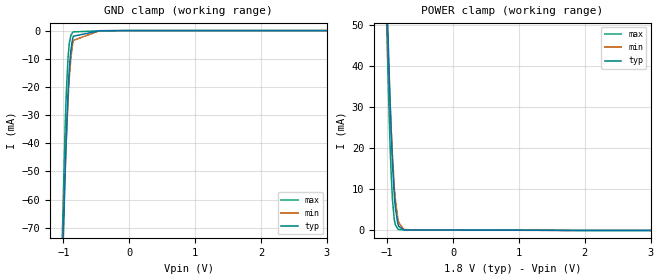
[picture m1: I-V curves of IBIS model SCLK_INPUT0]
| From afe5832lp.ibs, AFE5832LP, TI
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|   Model
[Model]   SCLK_INPUT0
Model_type   Input
Vinl = 0.45
Vinh = 1.35
|   typ   min   max
C_comp   1.431pF   1.417pF   1.444pF
[Voltage Range]   1.8   1.7   1.9
[Temperature Range]   25   85   -40
[Power Clamp Reference]   1.8   1.7   1.9
[GND Clamp Reference]   -0   -0   -0
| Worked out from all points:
|   POWER clamp passes 1 mA (typ) near -0.82 V on its own axis
[GND Clamp]
|   Voltage   I(typ)   I(min)   I(max)
-1.8V     -1.008A    -896.8mA   -1.105A
-1.017V   -87.02mA   -81.01mA   -72.85mA
-979.2mV  -54.6mA    -53.08mA   -38.24mA
-968.4mV  -46.35mA   -45.94mA   -30.03mA
-957.6mV  -38.67mA   -39.26mA   -22.79mA
-930.6mV  -22.47mA   -24.85mA   -9.685mA
-909mV    -13.08mA   -16mA      -4.192mA
-887.4mV  -6.947mA   -9.631mA   -1.721mA
-860.4mV  -2.882mA   -4.724mA   -628.3uA
-849.6mV  -2.005mA   -3.495mA   -455.1uA
-450mV    -65.8uA    -46.8uA    -96.36uA
3.595V    0A         0A         0A
[POWER Clamp]
|   Voltage   I(typ)   I(min)   I(max)
-1.8V     623.1mA    541mA      704mA
-1.006V   57.87mA    53.4mA     49.26mA
-1.001V   54.8mA     50.81mA    45.81mA
-968.4mV  37.48mA    36.16mA    26.85mA
-957.6mV  32.21mA    31.69mA    21.42mA
-941.4mV  24.92mA    25.43mA    14.38mA
-919.8mV  16.57mA    18.11mA    7.432mA
-892.8mV  8.753mA    10.84mA    2.687mA
-876.6mV  5.561mA    7.58mA     1.386mA
-838.8mV  1.662mA    2.886mA    353.2uA
-747mV    139.6uA    230.6uA    148.4uA
3.595V    0A         0A         0A
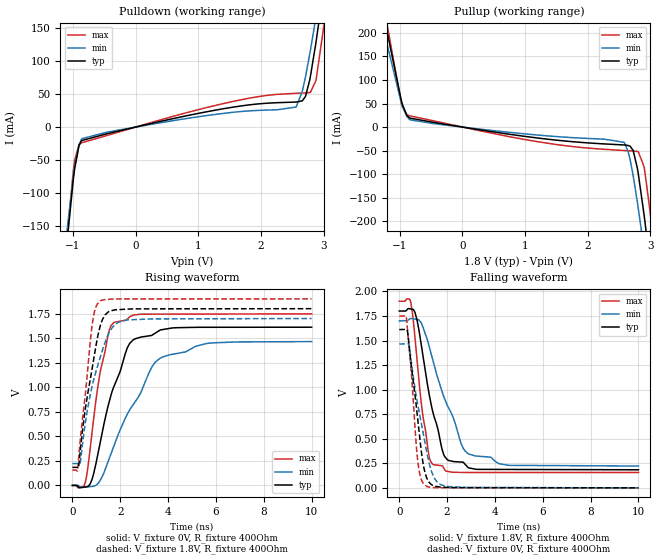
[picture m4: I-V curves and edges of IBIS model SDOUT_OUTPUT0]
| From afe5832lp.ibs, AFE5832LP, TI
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|   Model
[Model]   SDOUT_OUTPUT0
Model_type   Output
Polarity   Non-Inverting
Vmeas = 0.9
Vref = 0
Cref = 1pF
Rref = 100000
|   typ   min   max
C_comp   2.001pF   1.956pF   2.130pF
[Voltage Range]   1.8   1.7   1.9
[Temperature Range]   25   85   -40
[Pullup Reference]   1.8   1.7   1.9
[Pulldown Reference]   -0   -0   -0
[Power Clamp Reference]   1.8   1.7   1.9
[GND Clamp Reference]   -0   -0   -0
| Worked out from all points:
|   slope of the pulldown table from 0 to 0.27 V, typ, clamps not added: 45.8 ohm
|   slope of the pullup table from 0 to 0.27 V, typ, clamps not added: 47.1 ohm
|   falling waveform, V_fixture 1.8V, R_fixture 400Ohm: 20-80 % time 784ps typ, 1.21ns min, 492ps max; typ from 1.8 V to 0.184 V
|   rising waveform, V_fixture 0V, R_fixture 400Ohm: 20-80 % time 1.08ns typ, 1.68ns min, 660ps max; typ from 0 V to 1.61 V
|   rising waveform, V_fixture 1.8V, R_fixture 400Ohm: 20-80 % time 629ps typ, 817ps min, 437ps max; typ from 0.184 V to 1.8 V
|   falling waveform, V_fixture 0V, R_fixture 400Ohm: 20-80 % time 470ps typ, 650ps min, 317ps max; typ from 1.61 V to 0 V
[Pulldown]
|   Voltage   I(typ)   I(min)   I(max)
-1.8V     -1.018A    -906.1mA   -1.115A
-1.093V   -172.3mA   -155mA     -168.2mA
-973.8mV  -63.23mA   -60mA      -50.71mA
-903.6mV  -27.84mA   -26.74mA   -26.47mA
-855mV    -20.24mA   -17.48mA   -23.63mA
1.364V    27.13mA    20.28mA    34.75mA
2.563V    37.86mA    30.4mA     51.16mA
2.714V    47.25mA    77.4mA     51.7mA
2.785V    73.94mA    113.4mA    52.39mA
2.876V    126.6mA    165.5mA    69.88mA
3.011V    216.6mA    246.9mA    157.3mA
3.595V    642mA      620.3mA    642mA
[Pullup]
|   Voltage   I(typ)   I(min)   I(max)
-1.8V     641.6mA    556.4mA    725.3mA
-1.222V   214.8mA    186.5mA    231.9mA
-973.8mV  55.31mA    50.26mA    49.5mA
-833.4mV  18.85mA    15.3mA     23.68mA
1.213V    -23.47mA   -17.11mA   -31.32mA
2.579V    -38.05mA   -32.49mA   -49.86mA
2.644V    -39.1mA    -51.98mA   -50.33mA
2.725V    -50.52mA   -104mA     -50.92mA
2.806V    -99.41mA   -173.2mA   -52.48mA
2.898V    -186.2mA   -260.8mA   -84.29mA
3.038V    -340.3mA   -404.1mA   -232.5mA
3.595V    -1.015A    -1.015A    -974.6mA
[Ramp]
R_load = 400
|   typ   min   max
dV/dt_r   0.96676/1.0801e-09   0.878819/1.67694e-09   1.04844/6.60217e-10
dV/dt_f   0.96967/7.8361e-10   0.886724/1.21042e-09   1.04615/4.91379e-10
[Falling Waveform]
V_fixture = 1.8V
V_fixture_min = 1.7V
V_fixture_max = 1.9V
R_fixture = 400Ohm
C_fixture = 0F
|   Time   V(typ)   V(min)   V(max)
0s        1.8V       1.7V       1.9V
486.4ps   1.821V     1.724V     1.882V
744.7ps   1.706V     1.714V     1.298V
965.7ps   1.383V     1.651V     771.3mV
1.243ns   961.8mV    1.446V     324.3mV
1.392ns   783.2mV    1.311V     241mV
1.897ns   318.4mV    904.6mV    184.4mV
2.902ns   203.1mV    344.5mV    156.6mV
4.584ns   187.4mV    229mV      156.6mV
10ns      183.9mV    222.1mV    156.4mV
[Rising Waveform]
V_fixture = 0V
V_fixture_min = 0V
V_fixture_max = 0V
R_fixture = 400Ohm
C_fixture = 0F
|   Time   V(typ)   V(min)   V(max)
0s        15.47uV    18.84uV    13.33uV
546.4ps   -15.32mV   -17.41mV   39.25mV
807.2ps   52.69mV    -10.78mV   511.8mV
1.14ns    409.2mV    43.2mV     1.123V
1.518ns   833mV      259.7mV    1.561V
1.714ns   994.3mV    387.6mV    1.655V
2.393ns   1.446V     768.3mV    1.716V
3.689ns   1.584V     1.298V     1.744V
5.607ns   1.611V     1.445V     1.745V
10ns      1.611V     1.465V     1.747V
[Rising Waveform]
V_fixture = 1.8V
V_fixture_min = 1.7V
V_fixture_max = 1.9V
R_fixture = 400Ohm
C_fixture = 0F
|   Time   V(typ)   V(min)   V(max)
0s        183.9mV    221.9mV    156.4mV
211.4ps   180.7mV    222.2mV    152.3mV
327.5ps   350.5mV    232.4mV    458mV
543.8ps   784.8mV    639.7mV    938.3mV
816.2ps   1.178V     1.002V     1.618V
951.2ps   1.374V     1.132V     1.795V
1.14ns    1.602V     1.287V     1.875V
1.648ns   1.78V      1.601V     1.897V
2.286ns   1.795V     1.685V     1.899V
10ns      1.8V       1.7V       1.9V
[Falling Waveform]
|Gnd
V_fixture = 0V
V_fixture_min = 0V
V_fixture_max = 0V
R_fixture = 400Ohm
C_fixture = 0F
|   Time   V(typ)   V(min)   V(max)
0s        1.611V     1.465V     1.747V
294.9ps   1.613V     1.466V     1.735V
346.7ps   1.591V     1.466V     1.6V
421.1ps   1.42V      1.443V     1.404V
775.2ps   691.2mV    844mV      268mV
984ps     264.8mV    576.8mV    53.51mV
1.114ns   125.6mV    410.1mV    21.33mV
1.458ns   20.34mV    103.6mV    2.764mV
2.025ns   4.007mV    13.35mV    1.211mV
10ns      17.74uV    151.9uV    13.33uV
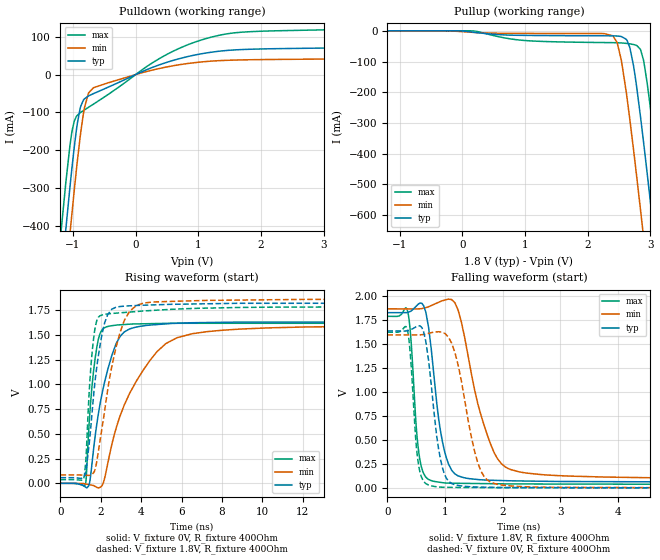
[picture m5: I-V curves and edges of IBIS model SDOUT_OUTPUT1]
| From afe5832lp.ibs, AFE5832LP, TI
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[Model]   SDOUT_OUTPUT1
Model_type   Output
Polarity   Non-Inverting
Vmeas = 0.9
Vref = 0
Cref = 1pF
Rref = 100000
|   typ   min   max
C_comp   2.001pF   1.956pF   2.130pF
[Voltage Range]   1.8   1.7   1.9
[Temperature Range]   25   85   -40
[Pullup Reference]   1.8   1.7   1.9
[Pulldown Reference]   -0   -0   -0
[Power Clamp Reference]   1.8   1.7   1.9
[GND Clamp Reference]   -0   -0   -0
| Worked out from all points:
|   slope of the pulldown table from 0 to 0.27 V, typ, clamps not added: 14.1 ohm
|   slope of the pullup table from 0 to 0.27 V, typ, clamps not added: 43.6 ohm
|   falling waveform, V_fixture 1.8V, R_fixture 400Ohm: 20-80 % time 225ps typ, 442ps min, 120ps max; typ from 1.82 V to 0.057 V
|   rising waveform, V_fixture 0V, R_fixture 400Ohm: 20-80 % time 937ps typ, 2.09ns min, 397ps max; typ from 0 V to 1.63 V
|   rising waveform, V_fixture 1.8V, R_fixture 400Ohm: 20-80 % time 595ps typ, 960ps min, 328ps max; typ from 0.057 V to 1.82 V
|   falling waveform, V_fixture 0V, R_fixture 400Ohm: 20-80 % time 194ps typ, 313ps min, 112ps max; typ from 1.63 V to 0 V
[Pulldown]
|   Voltage   I(typ)   I(min)   I(max)
-1.8V     -1.7A      -1.829A    -1.571A
-1.184V   -533.3mA   -662.8mA   -404.7mA
-1.114V   -408.9mA   -536.5mA   -285.6mA
-1.049V   -299.4mA   -423mA     -189.3mA
-1.028V   -264.6mA   -386.2mA   -163mA
-979.2mV  -191.4mA   -305.5mA   -122.9mA
-887.4mV  -90.69mA   -167.5mA   -101.3mA
-817.2mV  -64.11mA   -87.67mA   -93.32mA
-671.4mV  -50.21mA   -34.54mA   -78.02mA
381.6mV   25.99mA    16.27mA    42.59mA
1.138V    57.48mA    34.73mA    95.94mA
3.595V    71.51mA    41.94mA    120.3mA
[Pullup]
|   Voltage   I(typ)   I(min)   I(max)
-1.8V     320uA      320uA      320uA
154.8mV   -3.769mA   -4.528mA   127.5uA
2.261V    -15.97mA   -8.734mA   -37.98mA
2.466V    -16.59mA   -37.16mA   -38.57mA
2.612V    -27.02mA   -196.3mA   -40.61mA
2.731V    -114.3mA   -388.1mA   -44.43mA
2.844V    -284.3mA   -588mA     -61.97mA
2.887V    -357.5mA   -666.3mA   -93.37mA
3.001V    -559.4mA   -875.7mA   -253.6mA
3.092V    -728.6mA   -1.048A    -412.9mA
3.292V    -1.106A    -1.428A    -783.5mA
3.595V    -1.688A    -2.011A    -1.364A
[Ramp]
R_load = 400
|   typ   min   max
dV/dt_r   0.979272/9.36877e-10   0.954382/2.0873e-09   0.971519/3.96893e-10
dV/dt_f   1.05952/2.25052e-10   1.06702/4.42361e-10   1.04857/1.19593e-10
[Falling Waveform]
V_fixture = 1.8V
V_fixture_min = 1.7V
V_fixture_max = 1.9V
R_fixture = 400Ohm
C_fixture = 0F
|   Time   V(typ)   V(min)   V(max)
0s        1.823V     1.863V     1.785V
358.2ps   1.826V     1.862V     1.825V
518.7ps   1.9V       1.862V     516.2mV
630.8ps   1.895V     1.87V      149.8mV
985.1ps   402.9mV    1.952V     51.59mV
1.229ns   124mV      1.848V     47.44mV
1.569ns   86.76mV    879mV      45mV
1.909ns   77.42mV    306.4mV    42.55mV
2.659ns   68.98mV    138.8mV    40.11mV
40ns      56.96mV    84.34mV    37.03mV
[Rising Waveform]
V_fixture = 0V
V_fixture_min = 0V
V_fixture_max = 0V
R_fixture = 400Ohm
C_fixture = 0F
|   Time   V(typ)   V(min)   V(max)
0s        6.949nV    225.9nV    103.3pV
1.241ns   -37.65mV   -6.532mV   -7.456mV
1.462ns   25.82mV    -15.13mV   726.8mV
1.726ns   486.6mV    -32.41mV   1.273V
2.094ns   937.4mV    -10.45mV   1.558V
2.41ns    1.197V     266mV      1.589V
2.961ns   1.487V     684.8mV    1.603V
4.11ns    1.592V     1.147V     1.613V
6.52ns    1.624V     1.512V     1.618V
40ns      1.632V     1.591V     1.619V
[Rising Waveform]
V_fixture = 1.8V
V_fixture_min = 1.7V
V_fixture_max = 1.9V
R_fixture = 400Ohm
C_fixture = 0F
|   Time   V(typ)   V(min)   V(max)
0s        56.96mV    84.35mV    37.03mV
1.155ns   62.18mV    82.33mV    48.7mV
1.271ns   143.8mV    81.16mV    274.6mV
1.51ns    581mV      86.69mV    1.187V
1.682ns   971.5mV    120mV      1.527V
2.188ns   1.622V     730.1mV    1.708V
2.756ns   1.781V     1.375V     1.721V
3.428ns   1.795V     1.74V      1.732V
4.452ns   1.803V     1.831V     1.747V
40ns      1.823V     1.863V     1.785V
[Falling Waveform]
|Gnd
V_fixture = 0V
V_fixture_min = 0V
V_fixture_max = 0V
R_fixture = 400Ohm
C_fixture = 0F
|   Time   V(typ)   V(min)   V(max)
0s        1.633V     1.591V     1.62V
358.2ps   1.636V     1.591V     1.617V
503.6ps   1.677V     1.591V     431.1mV
600.4ps   1.667V     1.594V     102.8mV
716.2ps   1.326V     1.608V     29.72mV
922.3ps   299.7mV    1.622V     7.708mV
1.173ns   32.37mV    1.41V      4.593mV
1.626ns   7.354mV    173.6mV    2.762mV
2.181ns   3.229mV    18.06mV    1.539mV
40ns      59.5nV     -301.5nV   -359.7pV
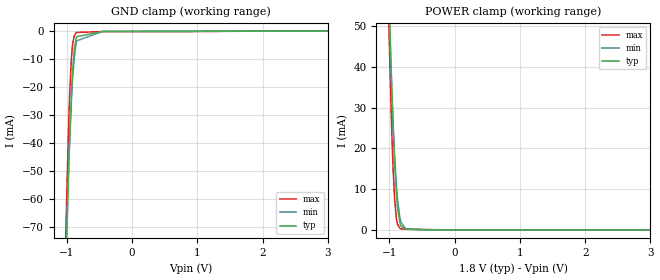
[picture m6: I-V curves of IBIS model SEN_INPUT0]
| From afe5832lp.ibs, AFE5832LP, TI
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|   Model
[Model]   SEN_INPUT0
Model_type   Input
Vinl = 0.45
Vinh = 1.35
|   typ   min   max
C_comp   1.431pF   1.417pF   1.444pF
[Voltage Range]   1.8   1.7   1.9
[Temperature Range]   25   85   -40
[Power Clamp Reference]   1.8   1.7   1.9
[GND Clamp Reference]   -0   -0   -0
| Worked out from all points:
|   POWER clamp passes 1 mA (typ) near -0.82 V on its own axis
[GND Clamp]
|   Voltage   I(typ)   I(min)   I(max)
-1.8V     -1.008A    -896.7mA   -1.105A
-1.017V   -87mA      -80.98mA   -72.84mA
-979.2mV  -54.59mA   -53.05mA   -38.24mA
-968.4mV  -46.34mA   -45.91mA   -30.02mA
-957.6mV  -38.66mA   -39.22mA   -22.78mA
-930.6mV  -22.45mA   -24.82mA   -9.678mA
-909mV    -13.07mA   -15.97mA   -4.188mA
-887.4mV  -6.936mA   -9.606mA   -1.721mA
-860.4mV  -2.874mA   -4.704mA   -633.6uA
-849.6mV  -1.999mA   -3.476mA   -462.6uA
-450mV    -120uA     -77.73uA   -192uA
3.595V    0A         0A         0A
[POWER Clamp]
|   Voltage   I(typ)   I(min)   I(max)
-1.8V     623.4mA    541.2mA    704.2mA
-1.006V   57.92mA    53.46mA    49.33mA
-1.001V   54.85mA    50.87mA    45.87mA
-968.4mV  37.53mA    36.21mA    26.92mA
-957.6mV  32.27mA    31.74mA    21.49mA
-941.4mV  24.98mA    25.48mA    14.45mA
-919.8mV  16.62mA    18.15mA    7.5mA
-876.6mV  5.613mA    7.624mA    1.451mA
-838.8mV  1.71mA     2.927mA    410.2uA
-747mV    173.3uA    261.2uA    182.2uA
-450mV    71.91uA    51.35uA    105.3uA
3.595V    0A         0A         0A
